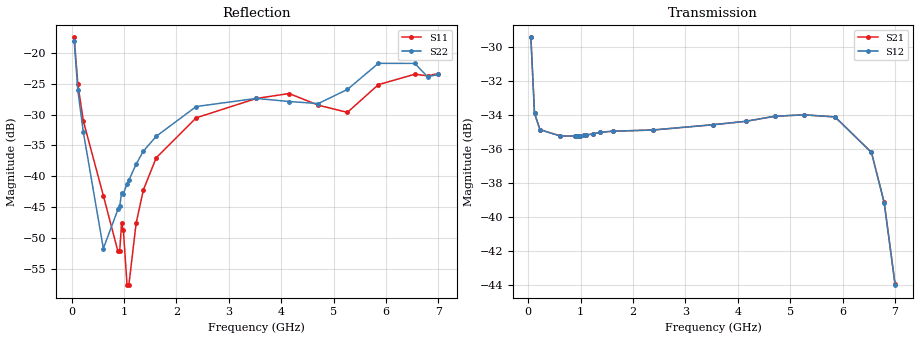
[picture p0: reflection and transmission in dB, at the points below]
! Integrated Device Technology
! Corporate Headquarters
! 6024 Silver Creek Valley Road
! San Jose, CA 95138  USA
! Phone:  1-408-284-8200
! Toll Free:  1-800-223-1366
! Webpage:  http://www.idt.com/
! Timing and RF Division
! 515 Groton Road, Suite 102
! Westford, MA 01886-6024
! Device:  F2258
! Description: Voltage Variable RF Attenuator
! Frequency:  50.0 -  6000.00 MHz
! Package:  3x3 mm Thin QFN Plastic Package: 16 pin
! Ports:  2 RF, 2 DC
!  Pin  1  = NC
!  Pin  2  = NC
!  Pin  3  = RF2  = Port 2
!  Pin  4  = GND
!  Pin  5  = Vdd
!  Pin  6  = NC
!  Pin  7  = VCTRL
!  Pin  8  = NC
!  Pin  9  = GND
!  Pin 10  = RF1  = Port 1
!  Pin 11  = NC
!  Pin 12  = NC
!  Pin 13  = NC
!  Pin 14  = NC
!  Pin 15  = NC
!  Pin 16  = NC
! Vcntrl:  2.100 Volts
! Vdd:  +3.300 Volts
! Current:  1.153 mA
! Data:  The device was measured on a the F2258 evaluation board which has
!  individual transmission lines to the RF pins.  Data was collected
!  using a calibrated network analyzer.  The evaluation board was
!  de-embedded using a TRL calibration technique.
!  The reference plane is the edge of the package pin.
! Misc:  SN 10
!  Action Tracker AT0285
! Date Measured:  2014-12-10
! Date:  2016-01-13  MJV
! Note:
!  Integrated Device Technology supplies this data as a sample of measured
!  data at the package pin for this product.  Your particular data for this
!  product may vary.
!  Data was taken at 25 degrees C.
!  Integrated Device Technology reserves the right to change this data at anytime.
!Freq_(GHz)  S11M_(dB)  S11P_(deg)  S21M_(dB)  S21P_(deg)  S12M_(dB)  S12P_(deg)  S22M_(dB)  S22P_(deg)
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# GHz S dB R 50
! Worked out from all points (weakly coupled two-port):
!   201 points, 50 MHz to 7 GHz, reference 50 ohm
!   highest |S21| = -29.44 dB at 50 MHz (marker M1); lowest = -44.0 dB at 7 GHz (marker M2)
!   lowest |S11| = -57.5 dB at 1.093 GHz (marker M3), VSWR 1.00, Z = 49.9 + j0.115 ohm
!   |S11| at or under -10 dB: start of sweep to end of sweep
!   |S22| runs from -51.6 to -18.1 dB; largest |S21 - S12| = 8.1e-05
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0.05  -17.55 -111.0  -29.44 -67.6  -29.44 -67.6  -18.14 -109.9
0.1195  -25.11 -106.9  -33.91 -36.3  -33.90 -36.3  -26.12 -101.1
0.22375  -31.03 -110.7  -34.86 -21.0  -34.86 -21.0  -32.82 -97.6
0.606  -43.09 -126.2  -35.22 -10.0  -35.23 -10.0  -51.63 -16.4
0.884  -52.07 166.6  -35.23 -8.5  -35.23 -8.5  -45.33 57.5
0.91875  -52.02 150.3  -35.23 -8.5  -35.22 -8.5  -44.83 58.8
0.9535  -47.58 -162.2  -35.23 -8.3  -35.24 -8.3  -42.62 85.6
0.98825  -48.72 -174.4  -35.22 -8.2  -35.22 -8.2  -42.81 81.9
1.05775  -57.44 153.3  -35.20 -8.1  -35.20 -8.1  -41.15 68.2
1.0925  -57.54 119.9  -35.18 -8.1  -35.18 -8.1  -40.63 65.6
1.2315  -47.55 46.5  -35.11 -8.1  -35.11 -8.1  -38.02 50.6
1.3705  -42.15 37.0  -35.01 -8.6  -35.02 -8.6  -35.90 44.7
1.61375  -37.00 32.8  -34.95 -9.9  -34.95 -9.9  -33.53 37.3
2.37825  -30.53 48.2  -34.88 -13.6  -34.88 -13.6  -28.71 34.1
3.525  -27.41 91.7  -34.57 -20.1  -34.57 -20.1  -27.40 60.6
4.1505  -26.61 104.9  -34.37 -24.6  -34.37 -24.6  -27.90 69.6
4.7065  -28.49 95.6  -34.07 -29.3  -34.07 -29.3  -28.23 52.3
5.2625  -29.66 54.4  -33.99 -35.5  -33.99 -35.5  -25.96 14.9
5.85325  -25.18 29.8  -34.11 -46.0  -34.11 -46.0  -21.74 -6.4
6.54825  -23.50 45.0  -36.19 -66.4  -36.20 -66.5  -21.75 -40.9
6.7915  -23.75 63.3  -39.13 -73.2  -39.16 -73.2  -23.90 -76.1
7  -23.38 84.5  -43.95 -62.1  -43.99 -61.4  -23.54 -128.9
